# Generated by FakeRAM 2.0
VERSION 5.7 ;
BUSBITCHARS "[]" ;
PROPERTYDEFINITIONS
  MACRO width INTEGER ;
  MACRO depth INTEGER ;
  MACRO banks INTEGER ;
END PROPERTYDEFINITIONS
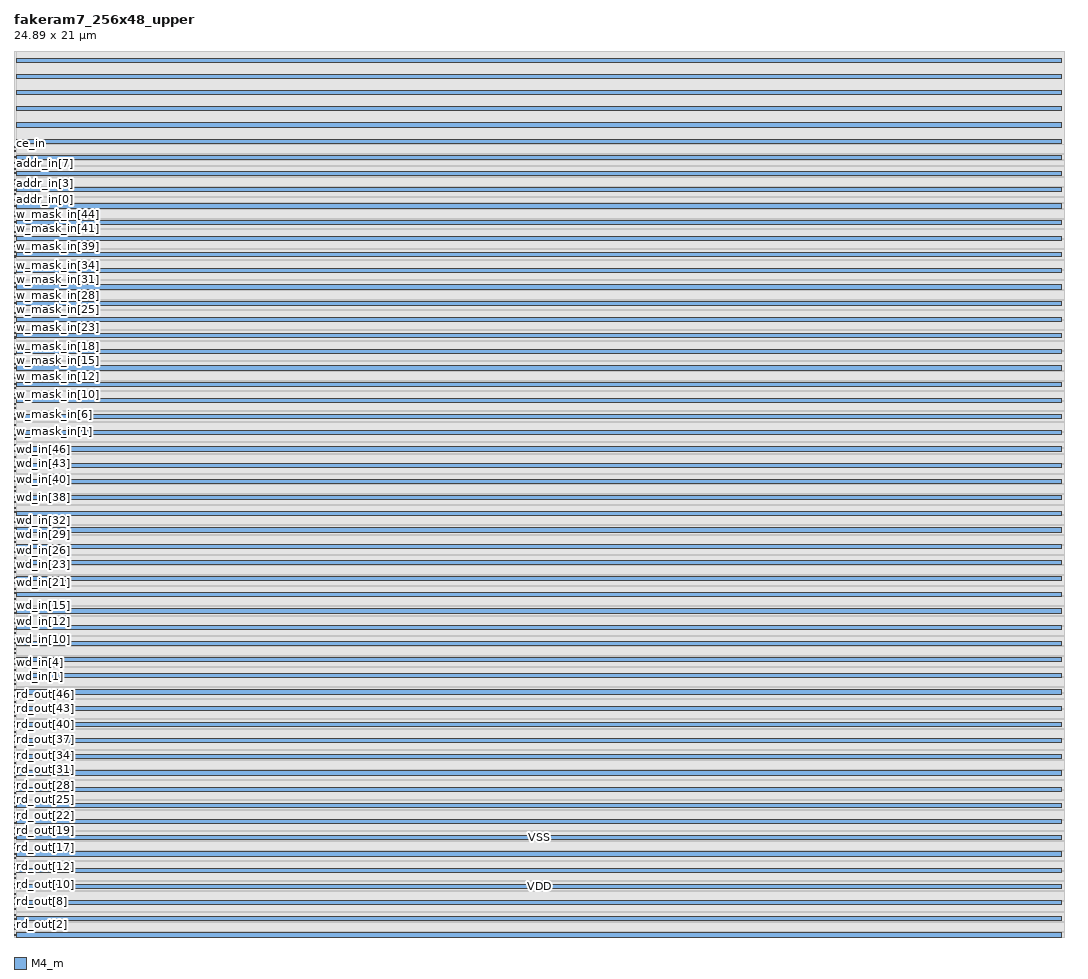
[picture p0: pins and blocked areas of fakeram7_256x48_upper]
MACRO fakeram7_256x48_upper
  PROPERTY width 48 ;
  PROPERTY depth 256 ;
  PROPERTY banks 2 ;
  FOREIGN fakeram7_256x48_upper 0 0 ;
  SYMMETRY X Y R90 ;
  SIZE 24.890 BY 21.000 ;
  CLASS BLOCK ;
  PIN rd_out[0]
    DIRECTION OUTPUT ;
    USE SIGNAL ;
    SHAPE ABUTMENT ;
    PORT
      LAYER M4_m ;
      RECT 0.000 0.039 0.024 0.063 ;
    END
  END rd_out[0]
  PIN rd_out[1]
    DIRECTION OUTPUT ;
    USE SIGNAL ;
    SHAPE ABUTMENT ;
    PORT
      LAYER M4_m ;
      RECT 0.000 0.183 0.024 0.207 ;
    END
  END rd_out[1]
  PIN rd_out[2]
    DIRECTION OUTPUT ;
    USE SIGNAL ;
    SHAPE ABUTMENT ;
    PORT
      LAYER M4_m ;
      RECT 0.000 0.279 0.024 0.303 ;
    END
  END rd_out[2]
  PIN rd_out[3]
    DIRECTION OUTPUT ;
    USE SIGNAL ;
    SHAPE ABUTMENT ;
    PORT
      LAYER M4_m ;
      RECT 0.000 0.423 0.024 0.447 ;
    END
  END rd_out[3]
  PIN rd_out[4]
    DIRECTION OUTPUT ;
    USE SIGNAL ;
    SHAPE ABUTMENT ;
    PORT
      LAYER M4_m ;
      RECT 0.000 0.519 0.024 0.543 ;
    END
  END rd_out[4]
  PIN rd_out[5]
    DIRECTION OUTPUT ;
    USE SIGNAL ;
    SHAPE ABUTMENT ;
    PORT
      LAYER M4_m ;
      RECT 0.000 0.663 0.024 0.687 ;
    END
  END rd_out[5]
  PIN rd_out[6]
    DIRECTION OUTPUT ;
    USE SIGNAL ;
    SHAPE ABUTMENT ;
    PORT
      LAYER M4_m ;
      RECT 0.000 0.759 0.024 0.783 ;
    END
  END rd_out[6]
  PIN rd_out[7]
    DIRECTION OUTPUT ;
    USE SIGNAL ;
    SHAPE ABUTMENT ;
    PORT
      LAYER M4_m ;
      RECT 0.000 0.903 0.024 0.927 ;
    END
  END rd_out[7]
  PIN rd_out[8]
    DIRECTION OUTPUT ;
    USE SIGNAL ;
    SHAPE ABUTMENT ;
    PORT
      LAYER M4_m ;
      RECT 0.000 0.999 0.024 1.023 ;
    END
  END rd_out[8]
  PIN rd_out[9]
    DIRECTION OUTPUT ;
    USE SIGNAL ;
    SHAPE ABUTMENT ;
    PORT
      LAYER M4_m ;
      RECT 0.000 1.143 0.024 1.167 ;
    END
  END rd_out[9]
  PIN rd_out[10]
    DIRECTION OUTPUT ;
    USE SIGNAL ;
    SHAPE ABUTMENT ;
    PORT
      LAYER M4_m ;
      RECT 0.000 1.239 0.024 1.263 ;
    END
  END rd_out[10]
  PIN rd_out[11]
    DIRECTION OUTPUT ;
    USE SIGNAL ;
    SHAPE ABUTMENT ;
    PORT
      LAYER M4_m ;
      RECT 0.000 1.383 0.024 1.407 ;
    END
  END rd_out[11]
  PIN rd_out[12]
    DIRECTION OUTPUT ;
    USE SIGNAL ;
    SHAPE ABUTMENT ;
    PORT
      LAYER M4_m ;
      RECT 0.000 1.479 0.024 1.503 ;
    END
  END rd_out[12]
  PIN rd_out[13]
    DIRECTION OUTPUT ;
    USE SIGNAL ;
    SHAPE ABUTMENT ;
    PORT
      LAYER M4_m ;
      RECT 0.000 1.623 0.024 1.647 ;
    END
  END rd_out[13]
  PIN rd_out[14]
    DIRECTION OUTPUT ;
    USE SIGNAL ;
    SHAPE ABUTMENT ;
    PORT
      LAYER M4_m ;
      RECT 0.000 1.719 0.024 1.743 ;
    END
  END rd_out[14]
  PIN rd_out[15]
    DIRECTION OUTPUT ;
    USE SIGNAL ;
    SHAPE ABUTMENT ;
    PORT
      LAYER M4_m ;
      RECT 0.000 1.863 0.024 1.887 ;
    END
  END rd_out[15]
  PIN rd_out[16]
    DIRECTION OUTPUT ;
    USE SIGNAL ;
    SHAPE ABUTMENT ;
    PORT
      LAYER M4_m ;
      RECT 0.000 1.959 0.024 1.983 ;
    END
  END rd_out[16]
  PIN rd_out[17]
    DIRECTION OUTPUT ;
    USE SIGNAL ;
    SHAPE ABUTMENT ;
    PORT
      LAYER M4_m ;
      RECT 0.000 2.103 0.024 2.127 ;
    END
  END rd_out[17]
  PIN rd_out[18]
    DIRECTION OUTPUT ;
    USE SIGNAL ;
    SHAPE ABUTMENT ;
    PORT
      LAYER M4_m ;
      RECT 0.000 2.199 0.024 2.223 ;
    END
  END rd_out[18]
  PIN rd_out[19]
    DIRECTION OUTPUT ;
    USE SIGNAL ;
    SHAPE ABUTMENT ;
    PORT
      LAYER M4_m ;
      RECT 0.000 2.343 0.024 2.367 ;
    END
  END rd_out[19]
  PIN rd_out[20]
    DIRECTION OUTPUT ;
    USE SIGNAL ;
    SHAPE ABUTMENT ;
    PORT
      LAYER M4_m ;
      RECT 0.000 2.439 0.024 2.463 ;
    END
  END rd_out[20]
  PIN rd_out[21]
    DIRECTION OUTPUT ;
    USE SIGNAL ;
    SHAPE ABUTMENT ;
    PORT
      LAYER M4_m ;
      RECT 0.000 2.583 0.024 2.607 ;
    END
  END rd_out[21]
  PIN rd_out[22]
    DIRECTION OUTPUT ;
    USE SIGNAL ;
    SHAPE ABUTMENT ;
    PORT
      LAYER M4_m ;
      RECT 0.000 2.679 0.024 2.703 ;
    END
  END rd_out[22]
  PIN rd_out[23]
    DIRECTION OUTPUT ;
    USE SIGNAL ;
    SHAPE ABUTMENT ;
    PORT
      LAYER M4_m ;
      RECT 0.000 2.823 0.024 2.847 ;
    END
  END rd_out[23]
  PIN rd_out[24]
    DIRECTION OUTPUT ;
    USE SIGNAL ;
    SHAPE ABUTMENT ;
    PORT
      LAYER M4_m ;
      RECT 0.000 2.919 0.024 2.943 ;
    END
  END rd_out[24]
  PIN rd_out[25]
    DIRECTION OUTPUT ;
    USE SIGNAL ;
    SHAPE ABUTMENT ;
    PORT
      LAYER M4_m ;
      RECT 0.000 3.063 0.024 3.087 ;
    END
  END rd_out[25]
  PIN rd_out[26]
    DIRECTION OUTPUT ;
    USE SIGNAL ;
    SHAPE ABUTMENT ;
    PORT
      LAYER M4_m ;
      RECT 0.000 3.159 0.024 3.183 ;
    END
  END rd_out[26]
  PIN rd_out[27]
    DIRECTION OUTPUT ;
    USE SIGNAL ;
    SHAPE ABUTMENT ;
    PORT
      LAYER M4_m ;
      RECT 0.000 3.303 0.024 3.327 ;
    END
  END rd_out[27]
  PIN rd_out[28]
    DIRECTION OUTPUT ;
    USE SIGNAL ;
    SHAPE ABUTMENT ;
    PORT
      LAYER M4_m ;
      RECT 0.000 3.399 0.024 3.423 ;
    END
  END rd_out[28]
  PIN rd_out[29]
    DIRECTION OUTPUT ;
    USE SIGNAL ;
    SHAPE ABUTMENT ;
    PORT
      LAYER M4_m ;
      RECT 0.000 3.543 0.024 3.567 ;
    END
  END rd_out[29]
  PIN rd_out[30]
    DIRECTION OUTPUT ;
    USE SIGNAL ;
    SHAPE ABUTMENT ;
    PORT
      LAYER M4_m ;
      RECT 0.000 3.639 0.024 3.663 ;
    END
  END rd_out[30]
  PIN rd_out[31]
    DIRECTION OUTPUT ;
    USE SIGNAL ;
    SHAPE ABUTMENT ;
    PORT
      LAYER M4_m ;
      RECT 0.000 3.783 0.024 3.807 ;
    END
  END rd_out[31]
  PIN rd_out[32]
    DIRECTION OUTPUT ;
    USE SIGNAL ;
    SHAPE ABUTMENT ;
    PORT
      LAYER M4_m ;
      RECT 0.000 3.879 0.024 3.903 ;
    END
  END rd_out[32]
  PIN rd_out[33]
    DIRECTION OUTPUT ;
    USE SIGNAL ;
    SHAPE ABUTMENT ;
    PORT
      LAYER M4_m ;
      RECT 0.000 4.023 0.024 4.047 ;
    END
  END rd_out[33]
  PIN rd_out[34]
    DIRECTION OUTPUT ;
    USE SIGNAL ;
    SHAPE ABUTMENT ;
    PORT
      LAYER M4_m ;
      RECT 0.000 4.119 0.024 4.143 ;
    END
  END rd_out[34]
  PIN rd_out[35]
    DIRECTION OUTPUT ;
    USE SIGNAL ;
    SHAPE ABUTMENT ;
    PORT
      LAYER M4_m ;
      RECT 0.000 4.263 0.024 4.287 ;
    END
  END rd_out[35]
  PIN rd_out[36]
    DIRECTION OUTPUT ;
    USE SIGNAL ;
    SHAPE ABUTMENT ;
    PORT
      LAYER M4_m ;
      RECT 0.000 4.359 0.024 4.383 ;
    END
  END rd_out[36]
  PIN rd_out[37]
    DIRECTION OUTPUT ;
    USE SIGNAL ;
    SHAPE ABUTMENT ;
    PORT
      LAYER M4_m ;
      RECT 0.000 4.503 0.024 4.527 ;
    END
  END rd_out[37]
  PIN rd_out[38]
    DIRECTION OUTPUT ;
    USE SIGNAL ;
    SHAPE ABUTMENT ;
    PORT
      LAYER M4_m ;
      RECT 0.000 4.599 0.024 4.623 ;
    END
  END rd_out[38]
  PIN rd_out[39]
    DIRECTION OUTPUT ;
    USE SIGNAL ;
    SHAPE ABUTMENT ;
    PORT
      LAYER M4_m ;
      RECT 0.000 4.743 0.024 4.767 ;
    END
  END rd_out[39]
  PIN rd_out[40]
    DIRECTION OUTPUT ;
    USE SIGNAL ;
    SHAPE ABUTMENT ;
    PORT
      LAYER M4_m ;
      RECT 0.000 4.839 0.024 4.863 ;
    END
  END rd_out[40]
  PIN rd_out[41]
    DIRECTION OUTPUT ;
    USE SIGNAL ;
    SHAPE ABUTMENT ;
    PORT
      LAYER M4_m ;
      RECT 0.000 4.983 0.024 5.007 ;
    END
  END rd_out[41]
  PIN rd_out[42]
    DIRECTION OUTPUT ;
    USE SIGNAL ;
    SHAPE ABUTMENT ;
    PORT
      LAYER M4_m ;
      RECT 0.000 5.079 0.024 5.103 ;
    END
  END rd_out[42]
  PIN rd_out[43]
    DIRECTION OUTPUT ;
    USE SIGNAL ;
    SHAPE ABUTMENT ;
    PORT
      LAYER M4_m ;
      RECT 0.000 5.223 0.024 5.247 ;
    END
  END rd_out[43]
  PIN rd_out[44]
    DIRECTION OUTPUT ;
    USE SIGNAL ;
    SHAPE ABUTMENT ;
    PORT
      LAYER M4_m ;
      RECT 0.000 5.319 0.024 5.343 ;
    END
  END rd_out[44]
  PIN rd_out[45]
    DIRECTION OUTPUT ;
    USE SIGNAL ;
    SHAPE ABUTMENT ;
    PORT
      LAYER M4_m ;
      RECT 0.000 5.463 0.024 5.487 ;
    END
  END rd_out[45]
  PIN rd_out[46]
    DIRECTION OUTPUT ;
    USE SIGNAL ;
    SHAPE ABUTMENT ;
    PORT
      LAYER M4_m ;
      RECT 0.000 5.559 0.024 5.583 ;
    END
  END rd_out[46]
  PIN rd_out[47]
    DIRECTION OUTPUT ;
    USE SIGNAL ;
    SHAPE ABUTMENT ;
    PORT
      LAYER M4_m ;
      RECT 0.000 5.703 0.024 5.727 ;
    END
  END rd_out[47]
  PIN wd_in[0]
    DIRECTION INPUT ;
    USE SIGNAL ;
    SHAPE ABUTMENT ;
    PORT
      LAYER M4_m ;
      RECT 0.000 5.847 0.024 5.871 ;
    END
  END wd_in[0]
  PIN wd_in[1]
    DIRECTION INPUT ;
    USE SIGNAL ;
    SHAPE ABUTMENT ;
    PORT
      LAYER M4_m ;
      RECT 0.000 5.991 0.024 6.015 ;
    END
  END wd_in[1]
  PIN wd_in[2]
    DIRECTION INPUT ;
    USE SIGNAL ;
    SHAPE ABUTMENT ;
    PORT
      LAYER M4_m ;
      RECT 0.000 6.087 0.024 6.111 ;
    END
  END wd_in[2]
  PIN wd_in[3]
    DIRECTION INPUT ;
    USE SIGNAL ;
    SHAPE ABUTMENT ;
    PORT
      LAYER M4_m ;
      RECT 0.000 6.231 0.024 6.255 ;
    END
  END wd_in[3]
  PIN wd_in[4]
    DIRECTION INPUT ;
    USE SIGNAL ;
    SHAPE ABUTMENT ;
    PORT
      LAYER M4_m ;
      RECT 0.000 6.327 0.024 6.351 ;
    END
  END wd_in[4]
  PIN wd_in[5]
    DIRECTION INPUT ;
    USE SIGNAL ;
    SHAPE ABUTMENT ;
    PORT
      LAYER M4_m ;
      RECT 0.000 6.471 0.024 6.495 ;
    END
  END wd_in[5]
  PIN wd_in[6]
    DIRECTION INPUT ;
    USE SIGNAL ;
    SHAPE ABUTMENT ;
    PORT
      LAYER M4_m ;
      RECT 0.000 6.567 0.024 6.591 ;
    END
  END wd_in[6]
  PIN wd_in[7]
    DIRECTION INPUT ;
    USE SIGNAL ;
    SHAPE ABUTMENT ;
    PORT
      LAYER M4_m ;
      RECT 0.000 6.711 0.024 6.735 ;
    END
  END wd_in[7]
  PIN wd_in[8]
    DIRECTION INPUT ;
    USE SIGNAL ;
    SHAPE ABUTMENT ;
    PORT
      LAYER M4_m ;
      RECT 0.000 6.807 0.024 6.831 ;
    END
  END wd_in[8]
  PIN wd_in[9]
    DIRECTION INPUT ;
    USE SIGNAL ;
    SHAPE ABUTMENT ;
    PORT
      LAYER M4_m ;
      RECT 0.000 6.951 0.024 6.975 ;
    END
  END wd_in[9]
  PIN wd_in[10]
    DIRECTION INPUT ;
    USE SIGNAL ;
    SHAPE ABUTMENT ;
    PORT
      LAYER M4_m ;
      RECT 0.000 7.047 0.024 7.071 ;
    END
  END wd_in[10]
  PIN wd_in[11]
    DIRECTION INPUT ;
    USE SIGNAL ;
    SHAPE ABUTMENT ;
    PORT
      LAYER M4_m ;
      RECT 0.000 7.191 0.024 7.215 ;
    END
  END wd_in[11]
  PIN wd_in[12]
    DIRECTION INPUT ;
    USE SIGNAL ;
    SHAPE ABUTMENT ;
    PORT
      LAYER M4_m ;
      RECT 0.000 7.287 0.024 7.311 ;
    END
  END wd_in[12]
  PIN wd_in[13]
    DIRECTION INPUT ;
    USE SIGNAL ;
    SHAPE ABUTMENT ;
    PORT
      LAYER M4_m ;
      RECT 0.000 7.431 0.024 7.455 ;
    END
  END wd_in[13]
  PIN wd_in[14]
    DIRECTION INPUT ;
    USE SIGNAL ;
    SHAPE ABUTMENT ;
    PORT
      LAYER M4_m ;
      RECT 0.000 7.527 0.024 7.551 ;
    END
  END wd_in[14]
  PIN wd_in[15]
    DIRECTION INPUT ;
    USE SIGNAL ;
    SHAPE ABUTMENT ;
    PORT
      LAYER M4_m ;
      RECT 0.000 7.671 0.024 7.695 ;
    END
  END wd_in[15]
  PIN wd_in[16]
    DIRECTION INPUT ;
    USE SIGNAL ;
    SHAPE ABUTMENT ;
    PORT
      LAYER M4_m ;
      RECT 0.000 7.767 0.024 7.791 ;
    END
  END wd_in[16]
  PIN wd_in[17]
    DIRECTION INPUT ;
    USE SIGNAL ;
    SHAPE ABUTMENT ;
    PORT
      LAYER M4_m ;
      RECT 0.000 7.911 0.024 7.935 ;
    END
  END wd_in[17]
  PIN wd_in[18]
    DIRECTION INPUT ;
    USE SIGNAL ;
    SHAPE ABUTMENT ;
    PORT
      LAYER M4_m ;
      RECT 0.000 8.007 0.024 8.031 ;
    END
  END wd_in[18]
  PIN wd_in[19]
    DIRECTION INPUT ;
    USE SIGNAL ;
    SHAPE ABUTMENT ;
    PORT
      LAYER M4_m ;
      RECT 0.000 8.151 0.024 8.175 ;
    END
  END wd_in[19]
  PIN wd_in[20]
    DIRECTION INPUT ;
    USE SIGNAL ;
    SHAPE ABUTMENT ;
    PORT
      LAYER M4_m ;
      RECT 0.000 8.247 0.024 8.271 ;
    END
  END wd_in[20]
  PIN wd_in[21]
    DIRECTION INPUT ;
    USE SIGNAL ;
    SHAPE ABUTMENT ;
    PORT
      LAYER M4_m ;
      RECT 0.000 8.391 0.024 8.415 ;
    END
  END wd_in[21]
  PIN wd_in[22]
    DIRECTION INPUT ;
    USE SIGNAL ;
    SHAPE ABUTMENT ;
    PORT
      LAYER M4_m ;
      RECT 0.000 8.487 0.024 8.511 ;
    END
  END wd_in[22]
  PIN wd_in[23]
    DIRECTION INPUT ;
    USE SIGNAL ;
    SHAPE ABUTMENT ;
    PORT
      LAYER M4_m ;
      RECT 0.000 8.631 0.024 8.655 ;
    END
  END wd_in[23]
  PIN wd_in[24]
    DIRECTION INPUT ;
    USE SIGNAL ;
    SHAPE ABUTMENT ;
    PORT
      LAYER M4_m ;
      RECT 0.000 8.727 0.024 8.751 ;
    END
  END wd_in[24]
  PIN wd_in[25]
    DIRECTION INPUT ;
    USE SIGNAL ;
    SHAPE ABUTMENT ;
    PORT
      LAYER M4_m ;
      RECT 0.000 8.871 0.024 8.895 ;
    END
  END wd_in[25]
  PIN wd_in[26]
    DIRECTION INPUT ;
    USE SIGNAL ;
    SHAPE ABUTMENT ;
    PORT
      LAYER M4_m ;
      RECT 0.000 8.967 0.024 8.991 ;
    END
  END wd_in[26]
  PIN wd_in[27]
    DIRECTION INPUT ;
    USE SIGNAL ;
    SHAPE ABUTMENT ;
    PORT
      LAYER M4_m ;
      RECT 0.000 9.111 0.024 9.135 ;
    END
  END wd_in[27]
  PIN wd_in[28]
    DIRECTION INPUT ;
    USE SIGNAL ;
    SHAPE ABUTMENT ;
    PORT
      LAYER M4_m ;
      RECT 0.000 9.207 0.024 9.231 ;
    END
  END wd_in[28]
  PIN wd_in[29]
    DIRECTION INPUT ;
    USE SIGNAL ;
    SHAPE ABUTMENT ;
    PORT
      LAYER M4_m ;
      RECT 0.000 9.351 0.024 9.375 ;
    END
  END wd_in[29]
  PIN wd_in[30]
    DIRECTION INPUT ;
    USE SIGNAL ;
    SHAPE ABUTMENT ;
    PORT
      LAYER M4_m ;
      RECT 0.000 9.447 0.024 9.471 ;
    END
  END wd_in[30]
  PIN wd_in[31]
    DIRECTION INPUT ;
    USE SIGNAL ;
    SHAPE ABUTMENT ;
    PORT
      LAYER M4_m ;
      RECT 0.000 9.591 0.024 9.615 ;
    END
  END wd_in[31]
  PIN wd_in[32]
    DIRECTION INPUT ;
    USE SIGNAL ;
    SHAPE ABUTMENT ;
    PORT
      LAYER M4_m ;
      RECT 0.000 9.687 0.024 9.711 ;
    END
  END wd_in[32]
  PIN wd_in[33]
    DIRECTION INPUT ;
    USE SIGNAL ;
    SHAPE ABUTMENT ;
    PORT
      LAYER M4_m ;
      RECT 0.000 9.831 0.024 9.855 ;
    END
  END wd_in[33]
  PIN wd_in[34]
    DIRECTION INPUT ;
    USE SIGNAL ;
    SHAPE ABUTMENT ;
    PORT
      LAYER M4_m ;
      RECT 0.000 9.927 0.024 9.951 ;
    END
  END wd_in[34]
  PIN wd_in[35]
    DIRECTION INPUT ;
    USE SIGNAL ;
    SHAPE ABUTMENT ;
    PORT
      LAYER M4_m ;
      RECT 0.000 10.071 0.024 10.095 ;
    END
  END wd_in[35]
  PIN wd_in[36]
    DIRECTION INPUT ;
    USE SIGNAL ;
    SHAPE ABUTMENT ;
    PORT
      LAYER M4_m ;
      RECT 0.000 10.167 0.024 10.191 ;
    END
  END wd_in[36]
  PIN wd_in[37]
    DIRECTION INPUT ;
    USE SIGNAL ;
    SHAPE ABUTMENT ;
    PORT
      LAYER M4_m ;
      RECT 0.000 10.311 0.024 10.335 ;
    END
  END wd_in[37]
  PIN wd_in[38]
    DIRECTION INPUT ;
    USE SIGNAL ;
    SHAPE ABUTMENT ;
    PORT
      LAYER M4_m ;
      RECT 0.000 10.407 0.024 10.431 ;
    END
  END wd_in[38]
  PIN wd_in[39]
    DIRECTION INPUT ;
    USE SIGNAL ;
    SHAPE ABUTMENT ;
    PORT
      LAYER M4_m ;
      RECT 0.000 10.551 0.024 10.575 ;
    END
  END wd_in[39]
  PIN wd_in[40]
    DIRECTION INPUT ;
    USE SIGNAL ;
    SHAPE ABUTMENT ;
    PORT
      LAYER M4_m ;
      RECT 0.000 10.647 0.024 10.671 ;
    END
  END wd_in[40]
  PIN wd_in[41]
    DIRECTION INPUT ;
    USE SIGNAL ;
    SHAPE ABUTMENT ;
    PORT
      LAYER M4_m ;
      RECT 0.000 10.791 0.024 10.815 ;
    END
  END wd_in[41]
  PIN wd_in[42]
    DIRECTION INPUT ;
    USE SIGNAL ;
    SHAPE ABUTMENT ;
    PORT
      LAYER M4_m ;
      RECT 0.000 10.887 0.024 10.911 ;
    END
  END wd_in[42]
  PIN wd_in[43]
    DIRECTION INPUT ;
    USE SIGNAL ;
    SHAPE ABUTMENT ;
    PORT
      LAYER M4_m ;
      RECT 0.000 11.031 0.024 11.055 ;
    END
  END wd_in[43]
  PIN wd_in[44]
    DIRECTION INPUT ;
    USE SIGNAL ;
    SHAPE ABUTMENT ;
    PORT
      LAYER M4_m ;
      RECT 0.000 11.127 0.024 11.151 ;
    END
  END wd_in[44]
  PIN wd_in[45]
    DIRECTION INPUT ;
    USE SIGNAL ;
    SHAPE ABUTMENT ;
    PORT
      LAYER M4_m ;
      RECT 0.000 11.271 0.024 11.295 ;
    END
  END wd_in[45]
  PIN wd_in[46]
    DIRECTION INPUT ;
    USE SIGNAL ;
    SHAPE ABUTMENT ;
    PORT
      LAYER M4_m ;
      RECT 0.000 11.367 0.024 11.391 ;
    END
  END wd_in[46]
  PIN wd_in[47]
    DIRECTION INPUT ;
    USE SIGNAL ;
    SHAPE ABUTMENT ;
    PORT
      LAYER M4_m ;
      RECT 0.000 11.511 0.024 11.535 ;
    END
  END wd_in[47]
  PIN w_mask_in[0]
    DIRECTION INPUT ;
    USE SIGNAL ;
    SHAPE ABUTMENT ;
    PORT
      LAYER M4_m ;
      RECT 0.000 11.655 0.024 11.679 ;
    END
  END w_mask_in[0]
  PIN w_mask_in[1]
    DIRECTION INPUT ;
    USE SIGNAL ;
    SHAPE ABUTMENT ;
    PORT
      LAYER M4_m ;
      RECT 0.000 11.799 0.024 11.823 ;
    END
  END w_mask_in[1]
  PIN w_mask_in[2]
    DIRECTION INPUT ;
    USE SIGNAL ;
    SHAPE ABUTMENT ;
    PORT
      LAYER M4_m ;
      RECT 0.000 11.895 0.024 11.919 ;
    END
  END w_mask_in[2]
  PIN w_mask_in[3]
    DIRECTION INPUT ;
    USE SIGNAL ;
    SHAPE ABUTMENT ;
    PORT
      LAYER M4_m ;
      RECT 0.000 12.039 0.024 12.063 ;
    END
  END w_mask_in[3]
  PIN w_mask_in[4]
    DIRECTION INPUT ;
    USE SIGNAL ;
    SHAPE ABUTMENT ;
    PORT
      LAYER M4_m ;
      RECT 0.000 12.135 0.024 12.159 ;
    END
  END w_mask_in[4]
  PIN w_mask_in[5]
    DIRECTION INPUT ;
    USE SIGNAL ;
    SHAPE ABUTMENT ;
    PORT
      LAYER M4_m ;
      RECT 0.000 12.279 0.024 12.303 ;
    END
  END w_mask_in[5]
  PIN w_mask_in[6]
    DIRECTION INPUT ;
    USE SIGNAL ;
    SHAPE ABUTMENT ;
    PORT
      LAYER M4_m ;
      RECT 0.000 12.375 0.024 12.399 ;
    END
  END w_mask_in[6]
  PIN w_mask_in[7]
    DIRECTION INPUT ;
    USE SIGNAL ;
    SHAPE ABUTMENT ;
    PORT
      LAYER M4_m ;
      RECT 0.000 12.519 0.024 12.543 ;
    END
  END w_mask_in[7]
  PIN w_mask_in[8]
    DIRECTION INPUT ;
    USE SIGNAL ;
    SHAPE ABUTMENT ;
    PORT
      LAYER M4_m ;
      RECT 0.000 12.615 0.024 12.639 ;
    END
  END w_mask_in[8]
  PIN w_mask_in[9]
    DIRECTION INPUT ;
    USE SIGNAL ;
    SHAPE ABUTMENT ;
    PORT
      LAYER M4_m ;
      RECT 0.000 12.759 0.024 12.783 ;
    END
  END w_mask_in[9]
  PIN w_mask_in[10]
    DIRECTION INPUT ;
    USE SIGNAL ;
    SHAPE ABUTMENT ;
    PORT
      LAYER M4_m ;
      RECT 0.000 12.855 0.024 12.879 ;
    END
  END w_mask_in[10]
  PIN w_mask_in[11]
    DIRECTION INPUT ;
    USE SIGNAL ;
    SHAPE ABUTMENT ;
    PORT
      LAYER M4_m ;
      RECT 0.000 12.999 0.024 13.023 ;
    END
  END w_mask_in[11]
  PIN w_mask_in[12]
    DIRECTION INPUT ;
    USE SIGNAL ;
    SHAPE ABUTMENT ;
    PORT
      LAYER M4_m ;
      RECT 0.000 13.095 0.024 13.119 ;
    END
  END w_mask_in[12]
  PIN w_mask_in[13]
    DIRECTION INPUT ;
    USE SIGNAL ;
    SHAPE ABUTMENT ;
    PORT
      LAYER M4_m ;
      RECT 0.000 13.239 0.024 13.263 ;
    END
  END w_mask_in[13]
  PIN w_mask_in[14]
    DIRECTION INPUT ;
    USE SIGNAL ;
    SHAPE ABUTMENT ;
    PORT
      LAYER M4_m ;
      RECT 0.000 13.335 0.024 13.359 ;
    END
  END w_mask_in[14]
  PIN w_mask_in[15]
    DIRECTION INPUT ;
    USE SIGNAL ;
    SHAPE ABUTMENT ;
    PORT
      LAYER M4_m ;
      RECT 0.000 13.479 0.024 13.503 ;
    END
  END w_mask_in[15]
  PIN w_mask_in[16]
    DIRECTION INPUT ;
    USE SIGNAL ;
    SHAPE ABUTMENT ;
    PORT
      LAYER M4_m ;
      RECT 0.000 13.575 0.024 13.599 ;
    END
  END w_mask_in[16]
  PIN w_mask_in[17]
    DIRECTION INPUT ;
    USE SIGNAL ;
    SHAPE ABUTMENT ;
    PORT
      LAYER M4_m ;
      RECT 0.000 13.719 0.024 13.743 ;
    END
  END w_mask_in[17]
  PIN w_mask_in[18]
    DIRECTION INPUT ;
    USE SIGNAL ;
    SHAPE ABUTMENT ;
    PORT
      LAYER M4_m ;
      RECT 0.000 13.815 0.024 13.839 ;
    END
  END w_mask_in[18]
  PIN w_mask_in[19]
    DIRECTION INPUT ;
    USE SIGNAL ;
    SHAPE ABUTMENT ;
    PORT
      LAYER M4_m ;
      RECT 0.000 13.959 0.024 13.983 ;
    END
  END w_mask_in[19]
  PIN w_mask_in[20]
    DIRECTION INPUT ;
    USE SIGNAL ;
    SHAPE ABUTMENT ;
    PORT
      LAYER M4_m ;
      RECT 0.000 14.055 0.024 14.079 ;
    END
  END w_mask_in[20]
  PIN w_mask_in[21]
    DIRECTION INPUT ;
    USE SIGNAL ;
    SHAPE ABUTMENT ;
    PORT
      LAYER M4_m ;
      RECT 0.000 14.199 0.024 14.223 ;
    END
  END w_mask_in[21]
  PIN w_mask_in[22]
    DIRECTION INPUT ;
    USE SIGNAL ;
    SHAPE ABUTMENT ;
    PORT
      LAYER M4_m ;
      RECT 0.000 14.295 0.024 14.319 ;
    END
  END w_mask_in[22]
  PIN w_mask_in[23]
    DIRECTION INPUT ;
    USE SIGNAL ;
    SHAPE ABUTMENT ;
    PORT
      LAYER M4_m ;
      RECT 0.000 14.439 0.024 14.463 ;
    END
  END w_mask_in[23]
  PIN w_mask_in[24]
    DIRECTION INPUT ;
    USE SIGNAL ;
    SHAPE ABUTMENT ;
    PORT
      LAYER M4_m ;
      RECT 0.000 14.535 0.024 14.559 ;
    END
  END w_mask_in[24]
  PIN w_mask_in[25]
    DIRECTION INPUT ;
    USE SIGNAL ;
    SHAPE ABUTMENT ;
    PORT
      LAYER M4_m ;
      RECT 0.000 14.679 0.024 14.703 ;
    END
  END w_mask_in[25]
  PIN w_mask_in[26]
    DIRECTION INPUT ;
    USE SIGNAL ;
    SHAPE ABUTMENT ;
    PORT
      LAYER M4_m ;
      RECT 0.000 14.775 0.024 14.799 ;
    END
  END w_mask_in[26]
  PIN w_mask_in[27]
    DIRECTION INPUT ;
    USE SIGNAL ;
    SHAPE ABUTMENT ;
    PORT
      LAYER M4_m ;
      RECT 0.000 14.919 0.024 14.943 ;
    END
  END w_mask_in[27]
  PIN w_mask_in[28]
    DIRECTION INPUT ;
    USE SIGNAL ;
    SHAPE ABUTMENT ;
    PORT
      LAYER M4_m ;
      RECT 0.000 15.015 0.024 15.039 ;
    END
  END w_mask_in[28]
  PIN w_mask_in[29]
    DIRECTION INPUT ;
    USE SIGNAL ;
    SHAPE ABUTMENT ;
    PORT
      LAYER M4_m ;
      RECT 0.000 15.159 0.024 15.183 ;
    END
  END w_mask_in[29]
  PIN w_mask_in[30]
    DIRECTION INPUT ;
    USE SIGNAL ;
    SHAPE ABUTMENT ;
    PORT
      LAYER M4_m ;
      RECT 0.000 15.255 0.024 15.279 ;
    END
  END w_mask_in[30]
  PIN w_mask_in[31]
    DIRECTION INPUT ;
    USE SIGNAL ;
    SHAPE ABUTMENT ;
    PORT
      LAYER M4_m ;
      RECT 0.000 15.399 0.024 15.423 ;
    END
  END w_mask_in[31]
  PIN w_mask_in[32]
    DIRECTION INPUT ;
    USE SIGNAL ;
    SHAPE ABUTMENT ;
    PORT
      LAYER M4_m ;
      RECT 0.000 15.495 0.024 15.519 ;
    END
  END w_mask_in[32]
  PIN w_mask_in[33]
    DIRECTION INPUT ;
    USE SIGNAL ;
    SHAPE ABUTMENT ;
    PORT
      LAYER M4_m ;
      RECT 0.000 15.639 0.024 15.663 ;
    END
  END w_mask_in[33]
  PIN w_mask_in[34]
    DIRECTION INPUT ;
    USE SIGNAL ;
    SHAPE ABUTMENT ;
    PORT
      LAYER M4_m ;
      RECT 0.000 15.735 0.024 15.759 ;
    END
  END w_mask_in[34]
  PIN w_mask_in[35]
    DIRECTION INPUT ;
    USE SIGNAL ;
    SHAPE ABUTMENT ;
    PORT
      LAYER M4_m ;
      RECT 0.000 15.879 0.024 15.903 ;
    END
  END w_mask_in[35]
  PIN w_mask_in[36]
    DIRECTION INPUT ;
    USE SIGNAL ;
    SHAPE ABUTMENT ;
    PORT
      LAYER M4_m ;
      RECT 0.000 15.975 0.024 15.999 ;
    END
  END w_mask_in[36]
  PIN w_mask_in[37]
    DIRECTION INPUT ;
    USE SIGNAL ;
    SHAPE ABUTMENT ;
    PORT
      LAYER M4_m ;
      RECT 0.000 16.119 0.024 16.143 ;
    END
  END w_mask_in[37]
  PIN w_mask_in[38]
    DIRECTION INPUT ;
    USE SIGNAL ;
    SHAPE ABUTMENT ;
    PORT
      LAYER M4_m ;
      RECT 0.000 16.215 0.024 16.239 ;
    END
  END w_mask_in[38]
  PIN w_mask_in[39]
    DIRECTION INPUT ;
    USE SIGNAL ;
    SHAPE ABUTMENT ;
    PORT
      LAYER M4_m ;
      RECT 0.000 16.359 0.024 16.383 ;
    END
  END w_mask_in[39]
  PIN w_mask_in[40]
    DIRECTION INPUT ;
    USE SIGNAL ;
    SHAPE ABUTMENT ;
    PORT
      LAYER M4_m ;
      RECT 0.000 16.455 0.024 16.479 ;
    END
  END w_mask_in[40]
  PIN w_mask_in[41]
    DIRECTION INPUT ;
    USE SIGNAL ;
    SHAPE ABUTMENT ;
    PORT
      LAYER M4_m ;
      RECT 0.000 16.599 0.024 16.623 ;
    END
  END w_mask_in[41]
  PIN w_mask_in[42]
    DIRECTION INPUT ;
    USE SIGNAL ;
    SHAPE ABUTMENT ;
    PORT
      LAYER M4_m ;
      RECT 0.000 16.695 0.024 16.719 ;
    END
  END w_mask_in[42]
  PIN w_mask_in[43]
    DIRECTION INPUT ;
    USE SIGNAL ;
    SHAPE ABUTMENT ;
    PORT
      LAYER M4_m ;
      RECT 0.000 16.839 0.024 16.863 ;
    END
  END w_mask_in[43]
  PIN w_mask_in[44]
    DIRECTION INPUT ;
    USE SIGNAL ;
    SHAPE ABUTMENT ;
    PORT
      LAYER M4_m ;
      RECT 0.000 16.935 0.024 16.959 ;
    END
  END w_mask_in[44]
  PIN w_mask_in[45]
    DIRECTION INPUT ;
    USE SIGNAL ;
    SHAPE ABUTMENT ;
    PORT
      LAYER M4_m ;
      RECT 0.000 17.079 0.024 17.103 ;
    END
  END w_mask_in[45]
  PIN w_mask_in[46]
    DIRECTION INPUT ;
    USE SIGNAL ;
    SHAPE ABUTMENT ;
    PORT
      LAYER M4_m ;
      RECT 0.000 17.175 0.024 17.199 ;
    END
  END w_mask_in[46]
  PIN w_mask_in[47]
    DIRECTION INPUT ;
    USE SIGNAL ;
    SHAPE ABUTMENT ;
    PORT
      LAYER M4_m ;
      RECT 0.000 17.319 0.024 17.343 ;
    END
  END w_mask_in[47]
  PIN addr_in[0]
    DIRECTION INPUT ;
    USE SIGNAL ;
    SHAPE ABUTMENT ;
    PORT
      LAYER M4_m ;
      RECT 0.000 17.463 0.024 17.487 ;
    END
  END addr_in[0]
  PIN addr_in[1]
    DIRECTION INPUT ;
    USE SIGNAL ;
    SHAPE ABUTMENT ;
    PORT
      LAYER M4_m ;
      RECT 0.000 17.607 0.024 17.631 ;
    END
  END addr_in[1]
  PIN addr_in[2]
    DIRECTION INPUT ;
    USE SIGNAL ;
    SHAPE ABUTMENT ;
    PORT
      LAYER M4_m ;
      RECT 0.000 17.703 0.024 17.727 ;
    END
  END addr_in[2]
  PIN addr_in[3]
    DIRECTION INPUT ;
    USE SIGNAL ;
    SHAPE ABUTMENT ;
    PORT
      LAYER M4_m ;
      RECT 0.000 17.847 0.024 17.871 ;
    END
  END addr_in[3]
  PIN addr_in[4]
    DIRECTION INPUT ;
    USE SIGNAL ;
    SHAPE ABUTMENT ;
    PORT
      LAYER M4_m ;
      RECT 0.000 17.943 0.024 17.967 ;
    END
  END addr_in[4]
  PIN addr_in[5]
    DIRECTION INPUT ;
    USE SIGNAL ;
    SHAPE ABUTMENT ;
    PORT
      LAYER M4_m ;
      RECT 0.000 18.087 0.024 18.111 ;
    END
  END addr_in[5]
  PIN addr_in[6]
    DIRECTION INPUT ;
    USE SIGNAL ;
    SHAPE ABUTMENT ;
    PORT
      LAYER M4_m ;
      RECT 0.000 18.183 0.024 18.207 ;
    END
  END addr_in[6]
  PIN addr_in[7]
    DIRECTION INPUT ;
    USE SIGNAL ;
    SHAPE ABUTMENT ;
    PORT
      LAYER M4_m ;
      RECT 0.000 18.327 0.024 18.351 ;
    END
  END addr_in[7]
  PIN we_in
    DIRECTION INPUT ;
    USE SIGNAL ;
    SHAPE ABUTMENT ;
    PORT
      LAYER M4_m ;
      RECT 0.000 18.471 0.024 18.495 ;
    END
  END we_in
  PIN ce_in
    DIRECTION INPUT ;
    USE SIGNAL ;
    SHAPE ABUTMENT ;
    PORT
      LAYER M4_m ;
      RECT 0.000 18.615 0.024 18.639 ;
    END
  END ce_in
  PIN clk
    DIRECTION INPUT ;
    USE SIGNAL ;
    SHAPE ABUTMENT ;
    PORT
      LAYER M4_m ;
      RECT 0.000 18.711 0.024 18.735 ;
    END
  END clk
  PIN VSS
    DIRECTION INOUT ;
    USE GROUND ;
    PORT
      LAYER M4_m ;
      RECT 0.048 0.000 24.842 0.096 ;
      RECT 0.048 0.768 24.842 0.864 ;
      RECT 0.048 1.536 24.842 1.632 ;
      RECT 0.048 2.304 24.842 2.400 ;
      RECT 0.048 3.072 24.842 3.168 ;
      RECT 0.048 3.840 24.842 3.936 ;
      RECT 0.048 4.608 24.842 4.704 ;
      RECT 0.048 5.376 24.842 5.472 ;
      RECT 0.048 6.144 24.842 6.240 ;
      RECT 0.048 6.912 24.842 7.008 ;
      RECT 0.048 7.680 24.842 7.776 ;
      RECT 0.048 8.448 24.842 8.544 ;
      RECT 0.048 9.216 24.842 9.312 ;
      RECT 0.048 9.984 24.842 10.080 ;
      RECT 0.048 10.752 24.842 10.848 ;
      RECT 0.048 11.520 24.842 11.616 ;
      RECT 0.048 12.288 24.842 12.384 ;
      RECT 0.048 13.056 24.842 13.152 ;
      RECT 0.048 13.824 24.842 13.920 ;
      RECT 0.048 14.592 24.842 14.688 ;
      RECT 0.048 15.360 24.842 15.456 ;
      RECT 0.048 16.128 24.842 16.224 ;
      RECT 0.048 16.896 24.842 16.992 ;
      RECT 0.048 17.664 24.842 17.760 ;
      RECT 0.048 18.432 24.842 18.528 ;
      RECT 0.048 19.200 24.842 19.296 ;
      RECT 0.048 19.968 24.842 20.064 ;
      RECT 0.048 20.736 24.842 20.832 ;
    END
  END VSS
  PIN VDD
    DIRECTION INOUT ;
    USE POWER ;
    PORT
      LAYER M4_m ;
      RECT 0.048 0.384 24.842 0.480 ;
      RECT 0.048 1.152 24.842 1.248 ;
      RECT 0.048 1.920 24.842 2.016 ;
      RECT 0.048 2.688 24.842 2.784 ;
      RECT 0.048 3.456 24.842 3.552 ;
      RECT 0.048 4.224 24.842 4.320 ;
      RECT 0.048 4.992 24.842 5.088 ;
      RECT 0.048 5.760 24.842 5.856 ;
      RECT 0.048 6.528 24.842 6.624 ;
      RECT 0.048 7.296 24.842 7.392 ;
      RECT 0.048 8.064 24.842 8.160 ;
      RECT 0.048 8.832 24.842 8.928 ;
      RECT 0.048 9.600 24.842 9.696 ;
      RECT 0.048 10.368 24.842 10.464 ;
      RECT 0.048 11.136 24.842 11.232 ;
      RECT 0.048 11.904 24.842 12.000 ;
      RECT 0.048 12.672 24.842 12.768 ;
      RECT 0.048 13.440 24.842 13.536 ;
      RECT 0.048 14.208 24.842 14.304 ;
      RECT 0.048 14.976 24.842 15.072 ;
      RECT 0.048 15.744 24.842 15.840 ;
      RECT 0.048 16.512 24.842 16.608 ;
      RECT 0.048 17.280 24.842 17.376 ;
      RECT 0.048 18.048 24.842 18.144 ;
      RECT 0.048 18.816 24.842 18.912 ;
      RECT 0.048 19.584 24.842 19.680 ;
      RECT 0.048 20.352 24.842 20.448 ;
    END
  END VDD
  OBS
    LAYER M1_m ;
    RECT 0 0 24.890 21.000 ;
    LAYER M2_m ;
    RECT 0 0 24.890 21.000 ;
    LAYER M3_m ;
    RECT 0.059 0.000 24.890 21.000 ;
    LAYER M4_m ;
    RECT 0.059 0.111 24.890 0.135 ;
    RECT 0.059 0.351 24.890 0.375 ;
    RECT 0.059 0.591 24.890 0.615 ;
    RECT 0.059 0.831 24.890 0.855 ;
    RECT 0.059 1.071 24.890 1.095 ;
    RECT 0.059 1.311 24.890 1.335 ;
    RECT 0.059 1.551 24.890 1.575 ;
    RECT 0.059 1.791 24.890 1.815 ;
    RECT 0.059 2.031 24.890 2.055 ;
    RECT 0.059 2.271 24.890 2.295 ;
    RECT 0.059 2.511 24.890 2.535 ;
    RECT 0.059 2.751 24.890 2.775 ;
    RECT 0.059 2.991 24.890 3.015 ;
    RECT 0.059 3.231 24.890 3.255 ;
    RECT 0.059 3.471 24.890 3.495 ;
    RECT 0.059 3.711 24.890 3.735 ;
    RECT 0.059 3.951 24.890 3.975 ;
    RECT 0.059 4.191 24.890 4.215 ;
    RECT 0.059 4.431 24.890 4.455 ;
    RECT 0.059 4.671 24.890 4.695 ;
    RECT 0.059 4.911 24.890 4.935 ;
    RECT 0.059 5.151 24.890 5.175 ;
    RECT 0.059 5.391 24.890 5.415 ;
    RECT 0.059 5.631 24.890 5.655 ;
    RECT 0.059 5.775 24.890 5.799 ;
    RECT 0.059 5.919 24.890 5.943 ;
    RECT 0.059 6.159 24.890 6.183 ;
    RECT 0.059 6.399 24.890 6.423 ;
    RECT 0.059 6.639 24.890 6.663 ;
    RECT 0.059 6.879 24.890 6.903 ;
    RECT 0.059 7.119 24.890 7.143 ;
    RECT 0.059 7.359 24.890 7.383 ;
    RECT 0.059 7.599 24.890 7.623 ;
    RECT 0.059 7.839 24.890 7.863 ;
    RECT 0.059 8.079 24.890 8.103 ;
    RECT 0.059 8.319 24.890 8.343 ;
    RECT 0.059 8.559 24.890 8.583 ;
    RECT 0.059 8.799 24.890 8.823 ;
    RECT 0.059 9.039 24.890 9.063 ;
    RECT 0.059 9.279 24.890 9.303 ;
    RECT 0.059 9.519 24.890 9.543 ;
    RECT 0.059 9.759 24.890 9.783 ;
    RECT 0.059 9.999 24.890 10.023 ;
    RECT 0.059 10.239 24.890 10.263 ;
    RECT 0.059 10.479 24.890 10.503 ;
    RECT 0.059 10.719 24.890 10.743 ;
    RECT 0.059 10.959 24.890 10.983 ;
    RECT 0.059 11.199 24.890 11.223 ;
    RECT 0.059 11.439 24.890 11.463 ;
    RECT 0.059 11.583 24.890 11.607 ;
    RECT 0.059 11.727 24.890 11.751 ;
    RECT 0.059 11.967 24.890 11.991 ;
    RECT 0.059 12.207 24.890 12.231 ;
    RECT 0.059 12.447 24.890 12.471 ;
    RECT 0.059 12.687 24.890 12.711 ;
    RECT 0.059 12.927 24.890 12.951 ;
    RECT 0.059 13.167 24.890 13.191 ;
    RECT 0.059 13.407 24.890 13.431 ;
    RECT 0.059 13.647 24.890 13.671 ;
    RECT 0.059 13.887 24.890 13.911 ;
    RECT 0.059 14.127 24.890 14.151 ;
    RECT 0.059 14.367 24.890 14.391 ;
    RECT 0.059 14.607 24.890 14.631 ;
    RECT 0.059 14.847 24.890 14.871 ;
    RECT 0.059 15.087 24.890 15.111 ;
    RECT 0.059 15.327 24.890 15.351 ;
    RECT 0.059 15.567 24.890 15.591 ;
    RECT 0.059 15.807 24.890 15.831 ;
    RECT 0.059 16.047 24.890 16.071 ;
    RECT 0.059 16.287 24.890 16.311 ;
    RECT 0.059 16.527 24.890 16.551 ;
    RECT 0.059 16.767 24.890 16.791 ;
    RECT 0.059 17.007 24.890 17.031 ;
    RECT 0.059 17.247 24.890 17.271 ;
    RECT 0.059 17.391 24.890 17.415 ;
    RECT 0.059 17.535 24.890 17.559 ;
    RECT 0.059 17.775 24.890 17.799 ;
    RECT 0.059 18.015 24.890 18.039 ;
    RECT 0.059 18.255 24.890 18.279 ;
    RECT 0.059 18.399 24.890 18.423 ;
    RECT 0.059 18.543 24.890 18.567 ;
    RECT 0.059 18.783 24.890 21.000 ;
  END
END fakeram7_256x48_upper

END LIBRARY
